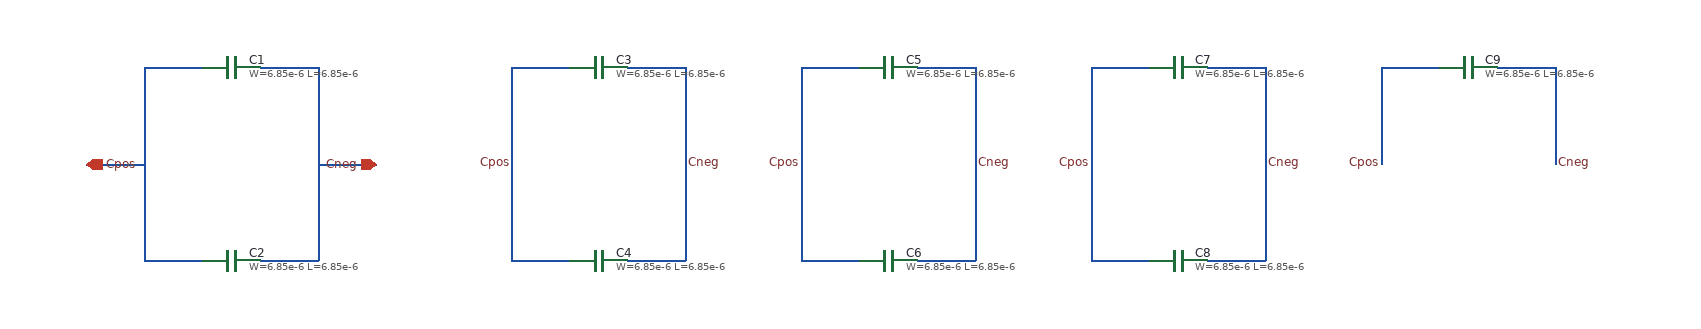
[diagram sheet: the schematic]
v {xschem version=3.4.8RC file_version=1.3}
G {}
K {}
V {}
S {}
F {}
E {}
N 700 -460 760 -460 {lab=Cneg}
N 580 -460 640 -460 {lab=Cpos}
N 580 -260 640 -260 {lab=Cpos}
N 700 -260 760 -260 {lab=Cneg}
N 320 -460 380 -460 {lab=Cneg}
N 200 -460 260 -460 {lab=Cpos}
N 200 -260 260 -260 {lab=Cpos}
N 320 -260 380 -260 {lab=Cneg}
N 380 -460 380 -260 {lab=Cneg}
N 200 -460 200 -260 {lab=Cpos}
N 140 -360 200 -360 {lab=Cpos}
N 380 -360 440 -360 {lab=Cneg}
N 580 -460 580 -260 {lab=Cpos}
N 760 -460 760 -260 {lab=Cneg}
N 1000 -460 1060 -460 {lab=Cneg}
N 880 -460 940 -460 {lab=Cpos}
N 880 -260 940 -260 {lab=Cpos}
N 1000 -260 1060 -260 {lab=Cneg}
N 880 -460 880 -260 {lab=Cpos}
N 1060 -460 1060 -260 {lab=Cneg}
N 1300 -460 1360 -460 {lab=Cneg}
N 1180 -460 1240 -460 {lab=Cpos}
N 1180 -260 1240 -260 {lab=Cpos}
N 1300 -260 1360 -260 {lab=Cneg}
N 1180 -460 1180 -260 {lab=Cpos}
N 1360 -460 1360 -260 {lab=Cneg}
N 1600 -460 1660 -460 {lab=Cneg}
N 1480 -460 1540 -460 {lab=Cpos}
N 1660 -460 1660 -360 {lab=Cneg}
N 1480 -460 1480 -360 {lab=Cpos}
C {iopin.sym} 140 -360 0 1 {name=p3 lab=Cpos}
C {iopin.sym} 440 -360 0 0 {name=p4 lab=Cneg}
C {lab_pin.sym} 580 -360 0 0 {name=p20 lab=Cpos}
C {lab_pin.sym} 760 -360 0 1 {name=p5 lab=Cneg}
C {lab_pin.sym} 880 -360 0 0 {name=p1 lab=Cpos}
C {lab_pin.sym} 1060 -360 0 1 {name=p2 lab=Cneg}
C {lab_pin.sym} 1180 -360 0 0 {name=p6 lab=Cpos}
C {lab_pin.sym} 1360 -360 0 1 {name=p7 lab=Cneg}
C {lab_pin.sym} 1480 -360 0 0 {name=p8 lab=Cpos}
C {lab_pin.sym} 1660 -360 0 1 {name=p9 lab=Cneg}
C {symbols/cap_mim_2f0fF.sym} 290 -460 3 0 {name=C1
W=6.85e-6
L=6.85e-6
model=cap_mim_2f0fF
spiceprefix=X
m=1}
C {symbols/cap_mim_2f0fF.sym} 290 -260 3 1 {name=C2
W=6.85e-6
L=6.85e-6
model=cap_mim_2f0fF
spiceprefix=X
m=1}
C {symbols/cap_mim_2f0fF.sym} 670 -460 3 0 {name=C3
W=6.85e-6
L=6.85e-6
model=cap_mim_2f0fF
spiceprefix=X
m=1}
C {symbols/cap_mim_2f0fF.sym} 670 -260 3 1 {name=C4
W=6.85e-6
L=6.85e-6
model=cap_mim_2f0fF
spiceprefix=X
m=1}
C {symbols/cap_mim_2f0fF.sym} 970 -460 3 0 {name=C5
W=6.85e-6
L=6.85e-6
model=cap_mim_2f0fF
spiceprefix=X
m=1}
C {symbols/cap_mim_2f0fF.sym} 970 -260 3 1 {name=C6
W=6.85e-6
L=6.85e-6
model=cap_mim_2f0fF
spiceprefix=X
m=1}
C {symbols/cap_mim_2f0fF.sym} 1270 -460 3 0 {name=C7
W=6.85e-6
L=6.85e-6
model=cap_mim_2f0fF
spiceprefix=X
m=1}
C {symbols/cap_mim_2f0fF.sym} 1270 -260 3 1 {name=C8
W=6.85e-6
L=6.85e-6
model=cap_mim_2f0fF
spiceprefix=X
m=1}
C {symbols/cap_mim_2f0fF.sym} 1570 -460 3 0 {name=C9
W=6.85e-6
L=6.85e-6
model=cap_mim_2f0fF
spiceprefix=X
m=1}
C {title.sym} 300 -80 0 0 {name=l1 author="Sayyad Arif"}
